VERSION 5.7 ;
  NOWIREEXTENSIONATPIN ON ;
  DIVIDERCHAR "/" ;
  BUSBITCHARS "[]" ;
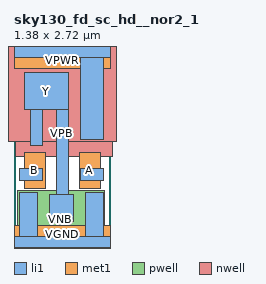
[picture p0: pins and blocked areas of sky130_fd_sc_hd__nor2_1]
MACRO sky130_fd_sc_hd__nor2_1
  CLASS CORE ;
  FOREIGN sky130_fd_sc_hd__nor2_1 ;
  ORIGIN 0.000 0.000 ;
  SIZE 1.380 BY 2.720 ;
  SITE unithd ;
  PIN A
    DIRECTION INPUT ;
    USE SIGNAL ;
    ANTENNAGATEAREA 0.229500 ;
    PORT
      LAYER li1 ;
        RECT 0.945 0.880 1.275 1.050 ;
      LAYER met1 ;
        RECT 0.935 0.765 1.235 1.275 ;
    END
  END A
  PIN B
    DIRECTION INPUT ;
    USE SIGNAL ;
    ANTENNAGATEAREA 0.229500 ;
    PORT
      LAYER li1 ;
        RECT 0.085 0.880 0.415 1.050 ;
      LAYER met1 ;
        RECT 0.145 0.765 0.445 1.275 ;
    END
  END B
  PIN VGND
    DIRECTION INOUT ;
    USE GROUND ;
    SHAPE ABUTMENT ;
    PORT
      LAYER li1 ;
        RECT 0.085 0.085 0.335 0.705 ;
        RECT 1.025 0.085 1.275 0.705 ;
        RECT 0.000 -0.085 1.380 0.085 ;
      LAYER met1 ;
        RECT 0.000 -0.240 1.380 0.240 ;
    END
  END VGND
  PIN VNB
    DIRECTION INOUT ;
    USE GROUND ;
    SHAPE ABUTMENT ;
    PORT
      LAYER pwell ;
        RECT 0.045 -0.085 1.300 0.740 ;
    END
  END VNB
  PIN VPB
    DIRECTION INOUT ;
    USE POWER ;
    SHAPE ABUTMENT ;
    PORT
      LAYER nwell ;
        RECT -0.190 1.435 1.570 2.910 ;
        RECT 0.015 1.225 1.415 1.435 ;
    END
  END VPB
  PIN VPWR
    DIRECTION INOUT ;
    USE POWER ;
    SHAPE ABUTMENT ;
    PORT
      LAYER li1 ;
        RECT 0.000 2.635 1.380 2.805 ;
        RECT 0.945 1.465 1.275 2.635 ;
      LAYER met1 ;
        RECT 0.000 2.480 1.380 2.960 ;
    END
  END VPWR
  PIN Y
    DIRECTION OUTPUT ;
    USE SIGNAL ;
    ANTENNADIFFAREA 0.412200 ;
    PORT
      LAYER li1 ;
        RECT 0.155 1.895 0.775 2.425 ;
        RECT 0.235 1.385 0.405 1.895 ;
        RECT 0.605 0.685 0.775 1.895 ;
        RECT 0.515 0.295 0.845 0.685 ;
    END
  END Y
END sky130_fd_sc_hd__nor2_1
END LIBRARY

